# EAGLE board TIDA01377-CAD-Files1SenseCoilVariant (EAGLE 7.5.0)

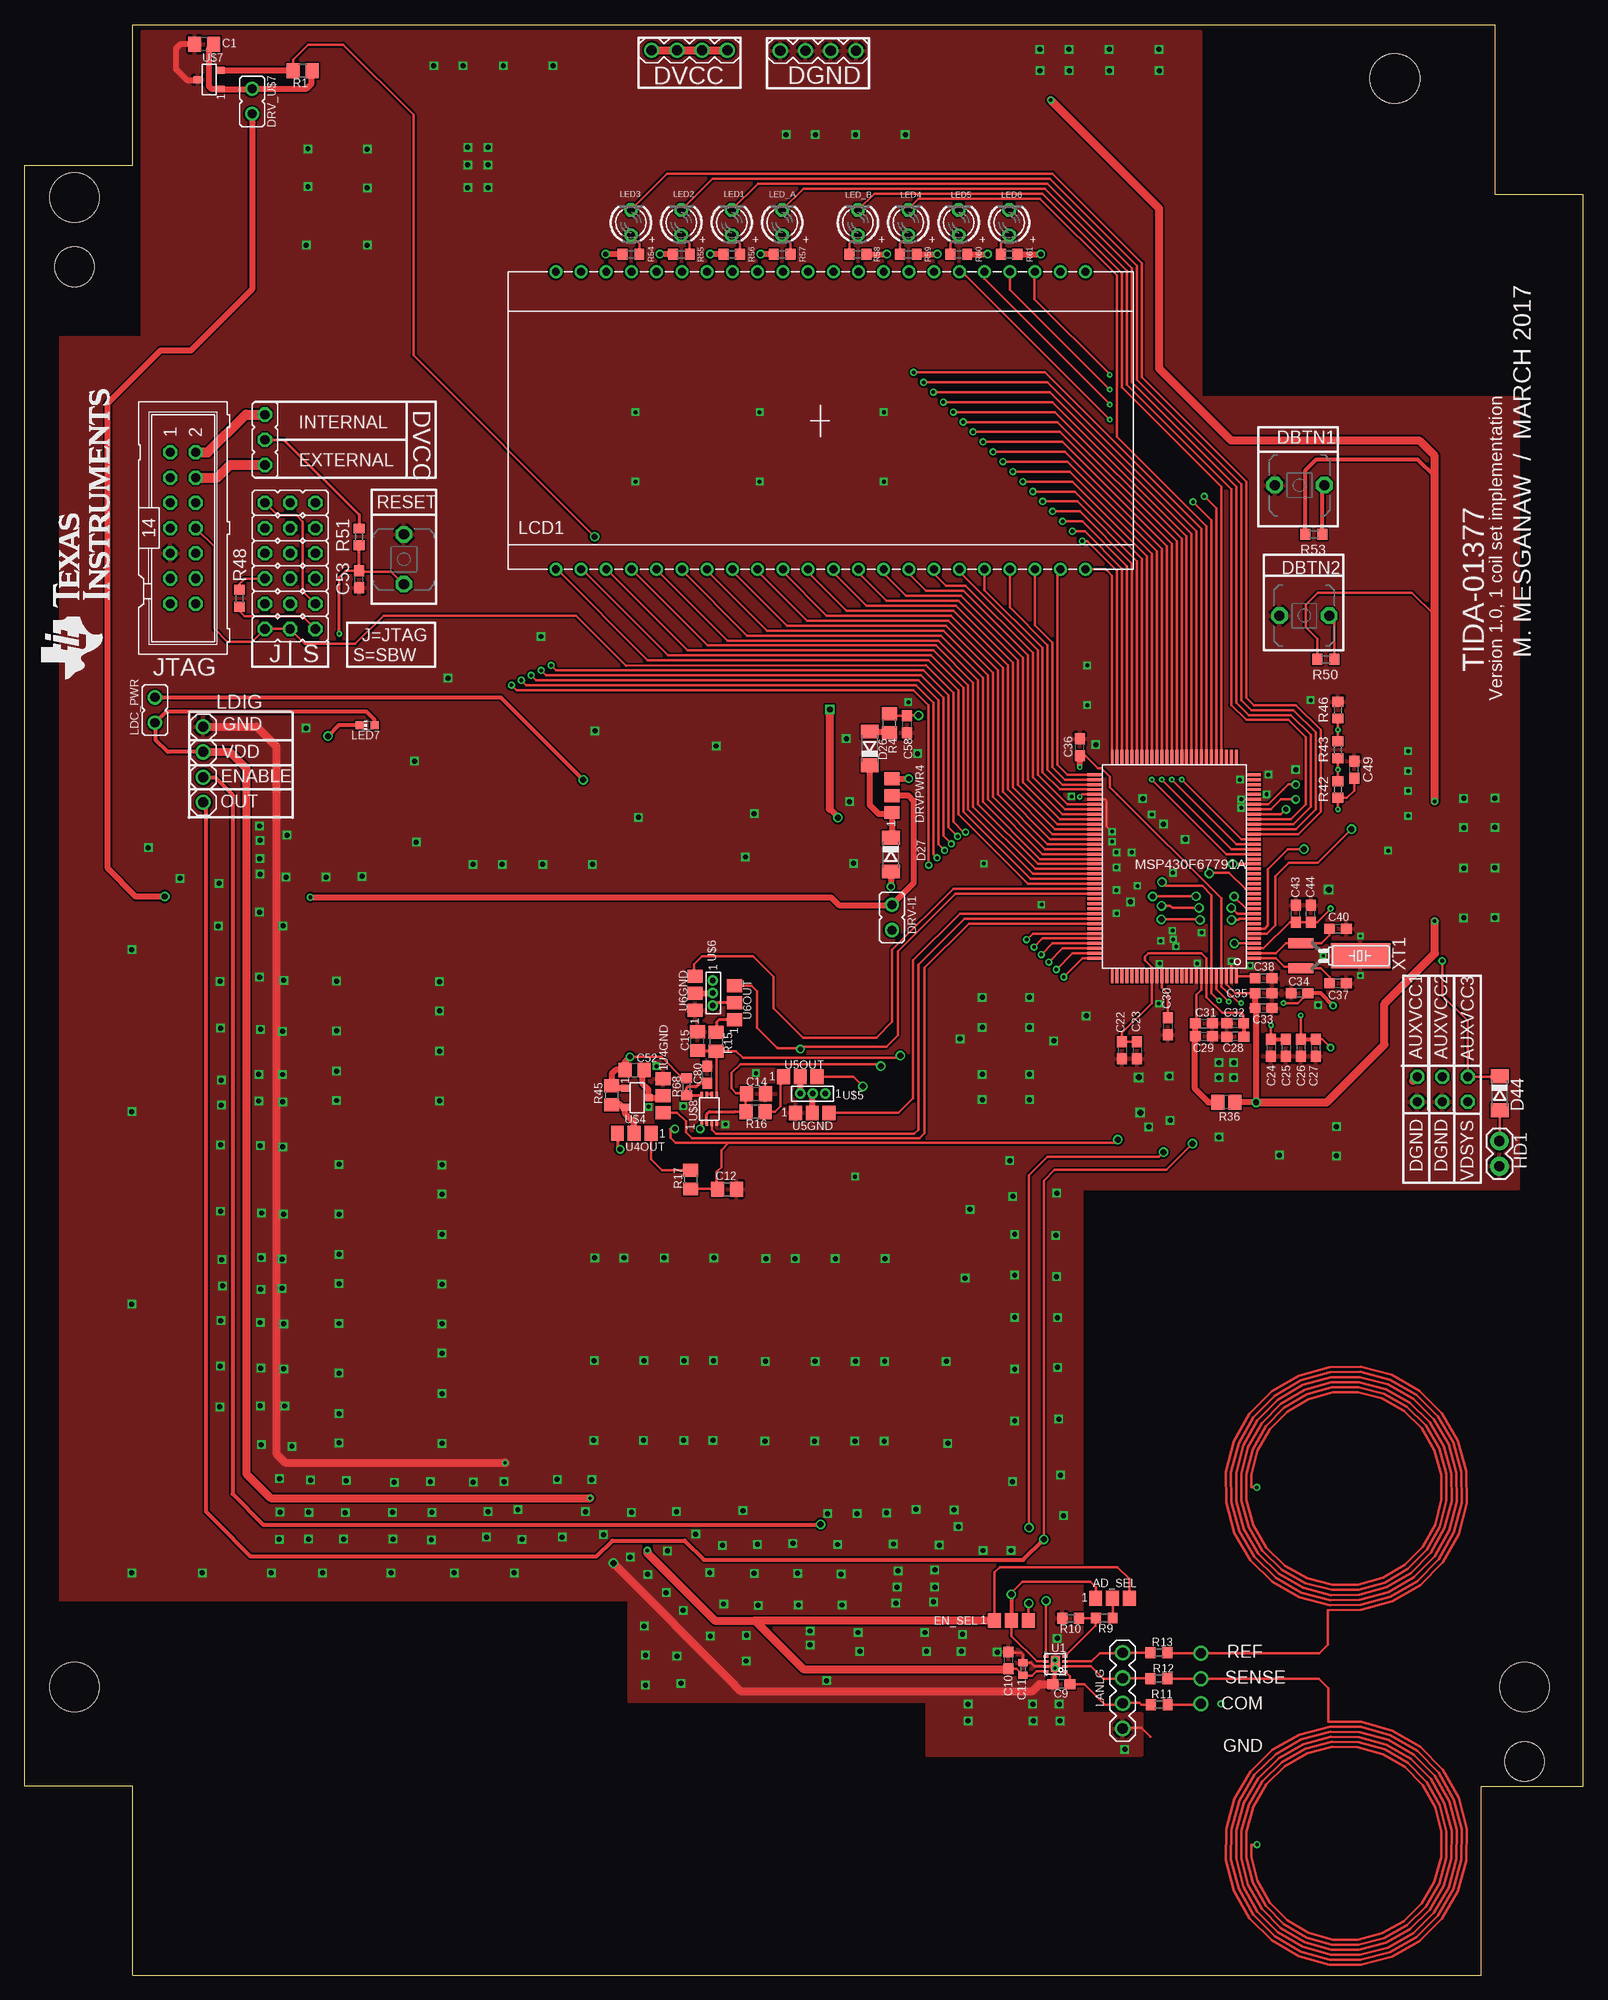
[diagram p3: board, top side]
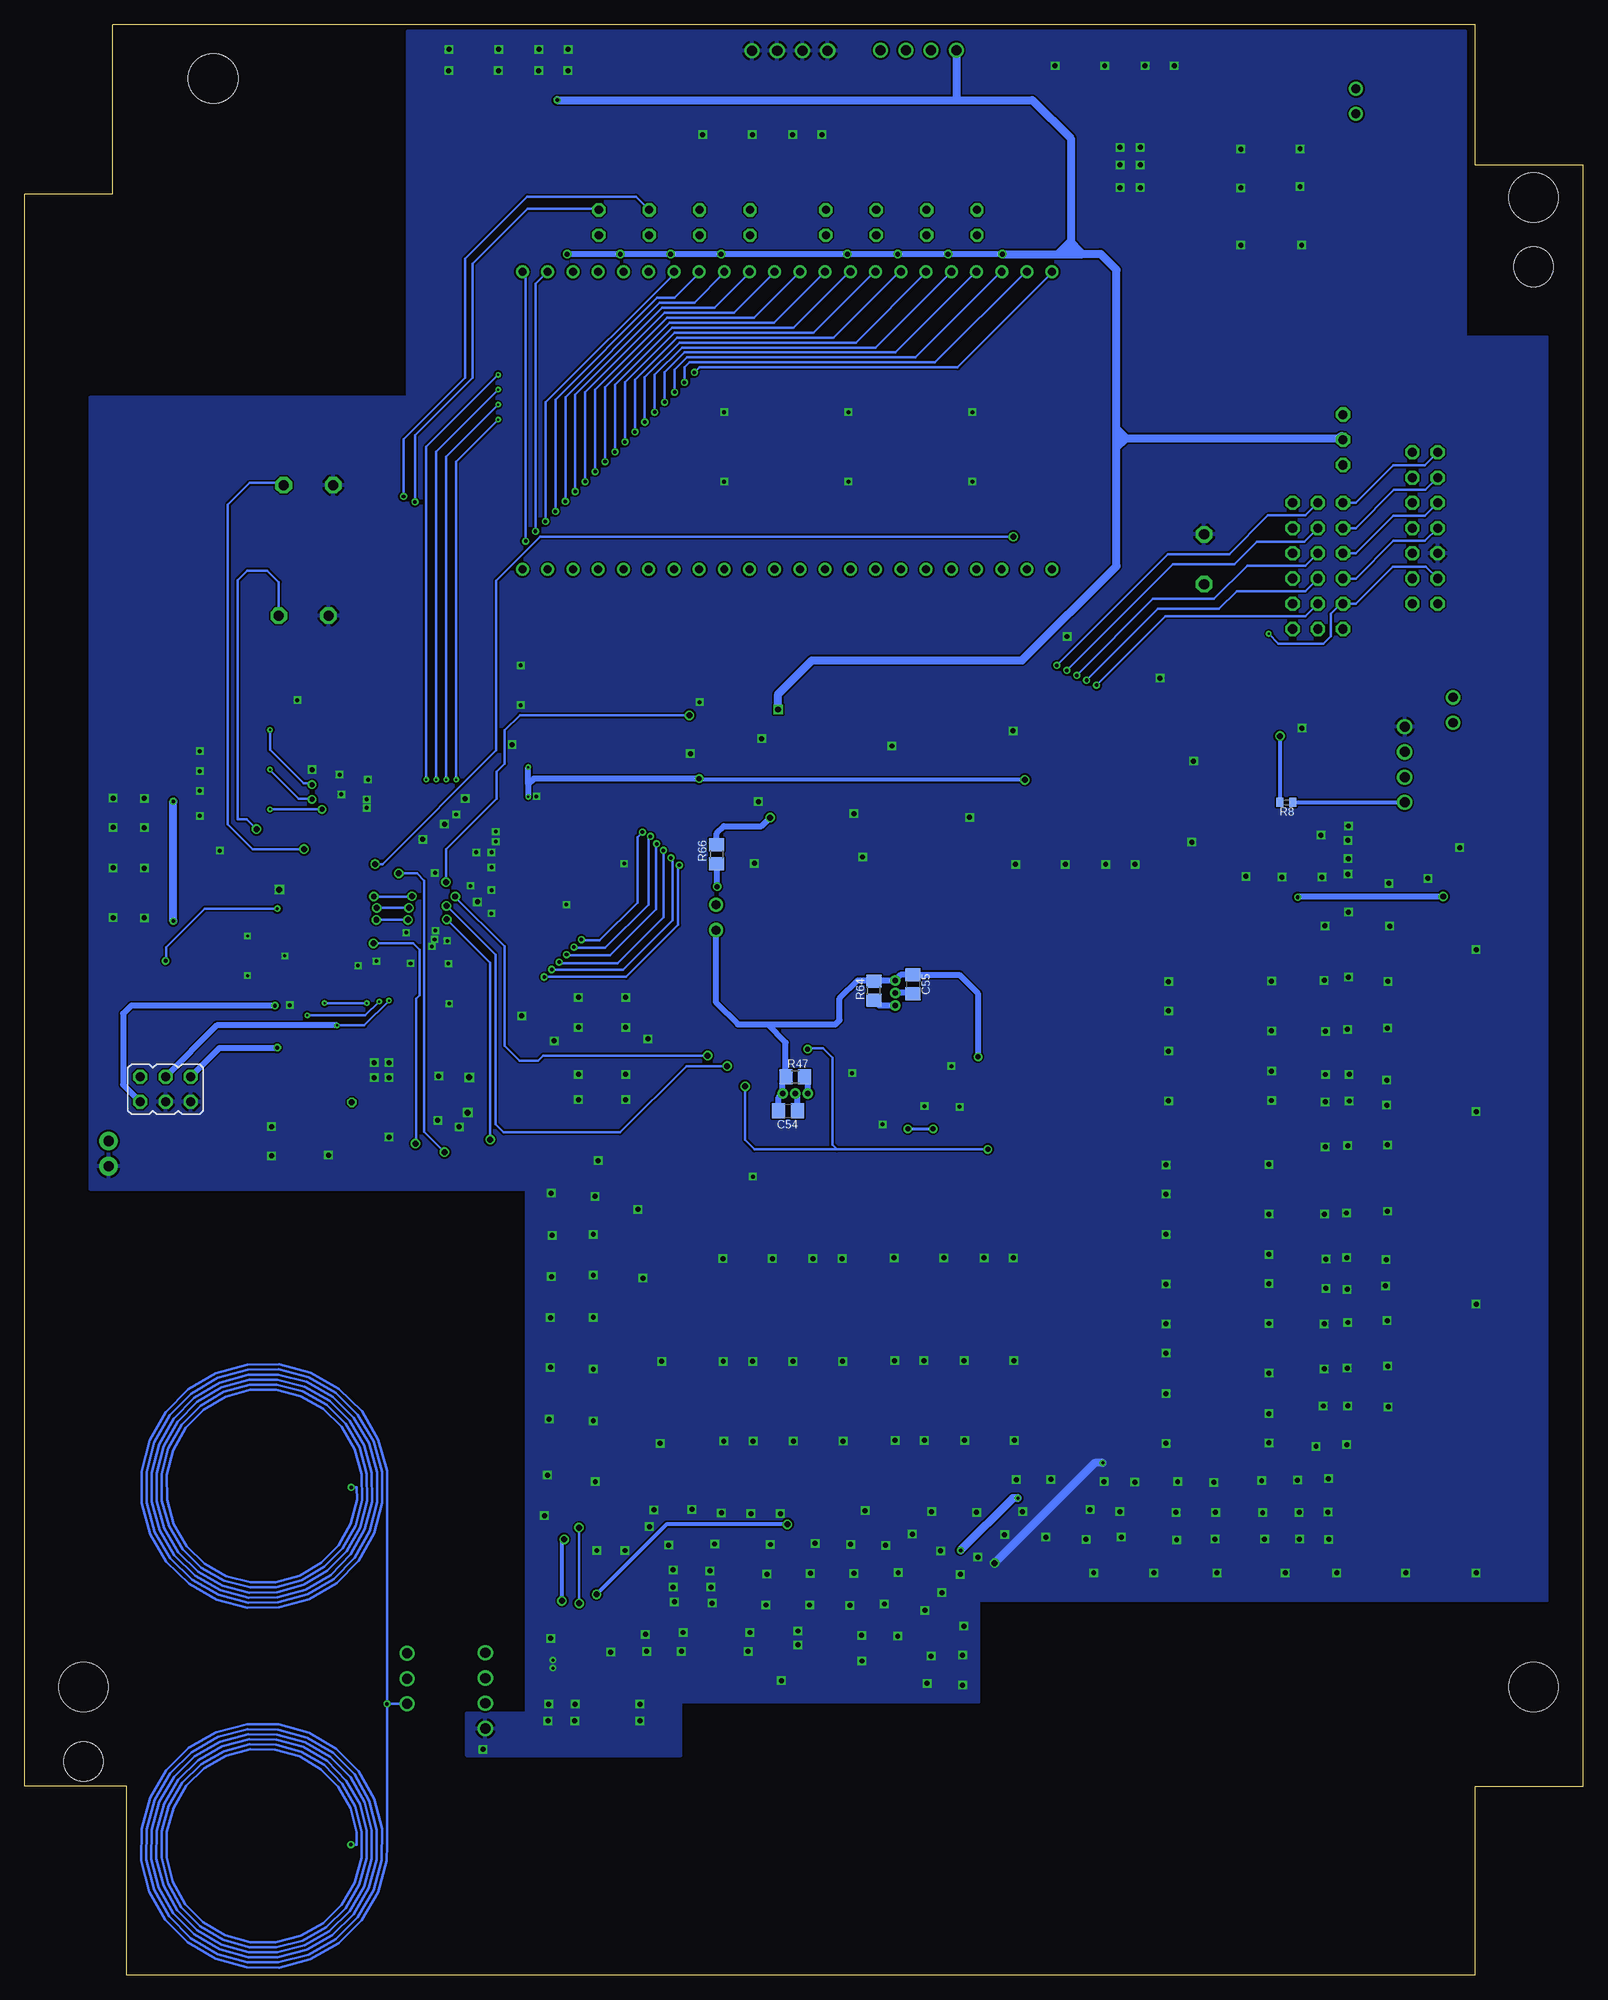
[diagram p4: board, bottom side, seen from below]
Size 156.94 x 196.36 mm. Coordinates in mm from the lower left corner, seen from the top.
Outline: 146.68,0 146.68,19 156.94,19 156.94,179.29 148.1,179.29 148.1,196.36 10.88,196.36 10.88,182.2 0,182.2 0,19 10.88,19 10.88,0 146.68,0
Copper layers (1*16): Top 0.0356mm / dielectric 1.5011mm / Bottom 0.0356mm
Design rules "SilverCircuits *": minimum track width 7mil, minimum drill 7.5mil, track to track 7mil, track to pad 7mil, pad to pad 7mil, via to via 7mil, smd to smd 0mil, copper to edge 20mil, drill to drill 8mil, minimum pad ring 10mil, minimum via ring 7mil, stop-mask expansion 4mil, vias tented up to drill 17mil, thermal gap 10mil
Holes 5 mm at 137.97,190.95 5,178.99 5,29 151.04,29
Holes 4 mm at 5,172 151.04,21.5

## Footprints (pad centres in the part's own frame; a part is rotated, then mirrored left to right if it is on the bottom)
A0R-JMP = smd 1.5 x 1.3: 1 0,1.7; 2 0,0; 3 0,-1.7
C0805 = smd 1.3 x 1.5: 1 -0.95,0; 2 0.95,0
C0603 = smd 1.1 x 1: 1 -0.85,0; 2 0.85,0
C0402 = smd 0.7 x 0.9: 1 -0.65,0; 2 0.65,0
SOD80C = smd 1.4 x 1.8: A 1.7,0; C -1.7,0
PBTH = drill 1.016 pad 1.676 octagon: 1 -0.001,0.001; 2 5.001,0.001
MA04-1 = drill 1.016: 1 -3.81,0; 2 -1.27,0; 3 1.27,0; 4 3.81,0
JP1 = drill 0.914: 1 0,-1.27; 2 0,1.27
1X02 = drill 1.016 pad 1.88: 1 0,0; 2 2.54,0
JP2 = drill 0.914 octagon: 1 -2.54,0; 2 0,0; 3 2.54,0
ML14 = drill 0.914 octagon: 1 -7.62,-1.27; 2 -7.62,1.27; 3 -5.08,-1.27; 4 -5.08,1.27; 5 -2.54,-1.27; 6 -2.54,1.27; 7 0,-1.27; 8 0,1.27; 9 2.54,-1.27; 10 2.54,1.27; 11 5.08,-1.27; 12 5.08,1.27; 13 7.62,-1.27; 14 7.62,1.27
TI_160SEG_LCD = drill 0.8: 1 4.826,0; 2 7.366,0; 3 9.906,0; 4 12.446,0; 5 14.986,0; 6 17.526,0; 7 20.066,0; 8 22.606,0; 9 25.146,0; 10 27.686,0; 11 30.226,0; 12 32.766,0; 13 35.306,0; 14 37.846,0; 15 40.386,0; 16 42.926,0; 17 45.466,0; 18 48.006,0; 19 50.546,0; 20 53.086,0; 21 55.626,0; 22 58.166,0; 23 58.166,29.972; 24 55.626,29.972; 29 42.926,29.972; 30 40.386,29.972; 31 37.846,29.972; 32 35.306,29.972; 33 32.766,29.972; 34 30.226,29.972; 35 27.686,29.972; 36 25.146,29.972; 37 22.606,29.972; 38 20.066,29.972; 39 17.526,29.972; 40 14.986,29.972; 41 12.446,29.972; 42 9.906,29.972; 43 7.366,29.972; 44 4.826,29.972; COM0 45.466,29.972; COM1 48.006,29.972; COM2 50.546,29.972; COM3 53.086,29.972
LED3MM = drill 0.813 octagon: A -1.27,0; K 1.27,0
CHIP-LED0603 = smd 0.8 x 0.8: A 0,-0.75; C 0,0.75
PEU128 = smd 0.3 x 1.4: 1 -9,-7.8; 2 -8.5,-7.8; 3 -8,-7.8; 4 -7.5,-7.8; 5 -7,-7.8; 6 -6.5,-7.8; 7 -6,-7.8; 8 -5.5,-7.8; 9 -5,-7.8; 10 -4.5,-7.8; 11 -4,-7.8; 12 -3.5,-7.8; 13 -3,-7.8; 14 -2.5,-7.8; 15 -2,-7.8; 16 -1.5,-7.8; 17 -1,-7.8; 18 -0.5,-7.8; 19 0,-7.8; 20 0.5,-7.8; 21 1,-7.8; 22 1.5,-7.8; 23 2,-7.8; 24 2.5,-7.8; 25 3,-7.8; 26 3.5,-7.8; 27 4,-7.8; 28 4.5,-7.8; 29 5,-7.8; 30 5.5,-7.8; 31 6,-7.8; 32 6.5,-7.8; 33 7,-7.8; 34 7.5,-7.8; 35 8,-7.8; 36 8.5,-7.8; 37 9,-7.8; 38 9.5,-7.8; 65 9.5,8.3; 66 9,8.3; 67 8.5,8.3; 68 8,8.3; 69 7.5,8.3; 70 7,8.3; 71 6.5,8.3; 72 6,8.3; 73 5.5,8.3; 74 5,8.3; 75 4.5,8.3; 76 4,8.3; 77 3.5,8.3; 78 3,8.3; 79 2.5,8.3; 80 2,8.3; 81 1.5,8.3; 82 1,8.3; 83 0.5,8.3; 84 0,8.3; 85 -0.5,8.3; 86 -1,8.3; 87 -1.5,8.3; 88 -2,8.3; 89 -2.5,8.3; 90 -3,8.3; 91 -3.5,8.3; 92 -4,8.3; 93 -4.5,8.3; 94 -5,8.3; 95 -5.5,8.3; 96 -6,8.3; 97 -6.5,8.3; 98 -7,8.3; 99 -7.5,8.3; 100 -8,8.3; 101 -8.5,8.3; 102 -9,8.3 | smd 1.4 x 0.3: 39 11.3,-6; 40 11.3,-5.5; 41 11.3,-5; 42 11.3,-4.5; 43 11.3,-4; 44 11.3,-3.5; 45 11.3,-3; 46 11.3,-2.5; 47 11.3,-2; 48 11.3,-1.5; 49 11.3,-1; 50 11.3,-0.5; 51 11.3,0; 52 11.3,0.5; 53 11.3,1; 54 11.3,1.5; 55 11.3,2; 56 11.3,2.5; 57 11.3,3; 58 11.3,3.5; 59 11.3,4; 60 11.3,4.5; 61 11.3,5; 62 11.3,5.5; 63 11.3,6; 64 11.3,6.5; 103 -10.8,6.5; 104 -10.8,6; 105 -10.8,5.5; 106 -10.8,5; 107 -10.8,4.5; 108 -10.8,4; 109 -10.8,3.5; 110 -10.8,3; 111 -10.8,2.5; 112 -10.8,2; 113 -10.8,1.5; 114 -10.8,1; 115 -10.8,0.5; 116 -10.8,0; 117 -10.8,-0.5; 118 -10.8,-1; 119 -10.8,-1.5; 120 -10.8,-2; 121 -10.8,-2.5; 122 -10.8,-3; 123 -10.8,-3.5; 124 -10.8,-4; 125 -10.8,-4.5; 126 -10.8,-5; 127 -10.8,-5.5; 128 -10.8,-6
R0805 = smd 1.3 x 1.5: 1 -0.95,0; 2 0.95,0
R0402 = smd 0.7 x 0.9: 1 -0.65,0; 2 0.65,0
R0603 = smd 1 x 1.1: 1 -0.85,0; 2 0.85,0
R0805' = smd 1.3 x 1.5: 1 -0.85,0; 2 0.85,0
JP3Q = drill 0.914 octagon: 1 -2.54,-1.27; 2 -2.54,1.27; 3 0,-1.27; 4 0,1.27; 5 2.54,-1.27; 6 2.54,1.27
DSG0008A = smd 0.508 x 0.254: 1 -0.95,0.75; 2 -0.95,0.25; 3 -0.95,-0.25; 4 -0.95,-0.75; 5 0.95,-0.75; 6 0.95,-0.25; 7 0.95,0.25; 8 0.95,0.75 | smd 0.889 x 1.6: 9 0,0
SOT23 = smd 0.7 x 0.8: 1 -0.92,-2.07; 2 0.98,-2.07; 3 0.03,0.275
SIP = drill 0.55: 1 0,0; 2 1.27,0; 3 2.54,0
DCU = smd 0.5 x 0.25: 1 1.39,-0.95; 2 1.39,-1.45; 3 1.39,-1.95; 4 1.39,-2.45; 5 4.29,-2.45; 6 4.29,-1.95; 7 4.29,-1.45; 8 4.29,-0.95
CM200T = smd 1 x 2.5: P1 -1.25,-5; P2 1.25,-5 | smd 2.5 x 6: P3 0,1

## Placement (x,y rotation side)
AD_SEL  0R-JUMPA  [A0R-JMP]  109.55,37.96 270 top
C1  DNP  [C0805]  18.06,194.4 180 top
C9  27pF  [C0603]  104.39,29.3 180 top
C10  1u  [C0603]  99.08,31.69 90 top
C11  0.1u  [C0402]  100.53,30.83 90 top
C12  DNP  [C0805]  70.71,79.14 0 top
C14  DNP  [C0805]  73.63,88.74 0 top
C15  DNP  [C0805]  67.74,94.05 90 top
C22  4.7uF  [C0603]  110.51,93.12 270 top
C23  100nF  [C0603]  112.01,93.12 270 top
C24  4.7uF  [C0603]  125.51,93.38 270 top
C25  100nF  [C0603]  127.01,93.38 270 top
C26  4.7uF  [C0603]  128.51,93.38 270 top
C27  100nF  [C0603]  130.01,93.38 270 top
C28  100nF  [C0603]  121.91,94.5 180 top
C29  4.7uF  [C0603]  118.76,94.53 0 top
C30  100nF  [C0603]  115.11,95.53 270 top
C31  100nF  [C0603]  118.76,95.83 0 top
C32  4.7uF  [C0603]  121.9,95.83 180 top
C33  100nF  [C0603]  124.76,97.38 0 top
C34  4.7uF  [C0603]  128.38,98.88 180 top
C35  4.7uF  [C0603]  124.76,98.88 0 top
C36  100nF  [C0603]  106.26,123.62 90 top
C37  12pF  [C0603]  132.26,99.88 0 top
C38  0.47uF  [C0603]  124.76,100.38 0 top
C40  12pF  [C0603]  132.26,105.38 0 top
C43  100nF  [C0603]  128.01,106.88 90 top
C44  0.47uF  [C0603]  129.51,106.88 90 top
C49  4.7uF  [C0603]  133.88,121.38 90 top
C52  DNP  [C0805]  61.4,91.14 0 top
C53  0.1uF  [C0603]  33.67,140.56 90 top
C54  DNP  [C0805]  80.08,87.02 0 bottom
C55  DNP  [C0805]  67.51,99.77 270 bottom
C58  DNP  [C0603]  88.82,125.95 270 top
C80  DNP  [C0603]  68.73,90.67 90 top
D26  PMLL4148  [SOD80C]  85.09,123.51 90 top
D27  PMLL4148  [SOD80C]  87.22,112.82 270 top
D44  [SOD80C]  148.54,88.79 270 top
DBTN1  [PBTH]  125.88,150.02 0 top
DBTN2  [PBTH]  126.36,136.88 0 top
DGND  [MA04-1]  79.9,193.75 0 top
DRV-I1  [JP1]  87.32,106.49 0 top
DRV_U$7  [JP1]  22.88,188.66 180 top
DRVPWR4  0R-JUMPA  [A0R-JMP]  87.32,118.76 0 top
DVCC  [MA04-1]  66.94,193.8 0 top
EN_SEL  0R-JUMPA  [A0R-JMP]  99.36,35.7 270 top
HD1  [1X02]  148.51,81.45 90 top
JP4  [JP2]  26.72,135.54 180 top
JP5  [JP2]  26.72,138.08 180 top
JP6  [JP2]  26.72,140.62 180 top
JP7  [JP2]  26.72,143.16 180 top
JP8  [JP2]  26.72,145.7 180 top
JP9  [JP2]  26.72,148.24 180 top
JP10  [JP2]  24.18,154.59 270 top
JTAG  [ML14]  15.93,145.7 270 top
LANLG  [MA04-1]  110.56,28.64 90 top
LCD1  TI_160SEG_LCD  [TI_160SEG_LCD]  48.65,141.53 0 top
LDC_PWR  [JP1]  13.1,127.37 0 top
LDIG  [MA04-1]  17.98,121.89 90 top
LED1  [LED3MM]  71.2,176.46 90 top
LED2  [LED3MM]  66.12,176.46 90 top
LED3  [LED3MM]  61.04,176.46 90 top
LED4  [LED3MM]  88.98,176.46 90 top
LED5  [LED3MM]  94.06,176.46 90 top
LED6  [LED3MM]  99.14,176.46 90 top
LED7  [CHIP-LED0603]  34.47,125.85 90 top
LED_A  [LED3MM]  76.28,176.46 90 top
LED_B  [LED3MM]  83.9,176.46 90 top
MSP430F67791A  MSP430F6779AIPEU  [PEU128]  116.01,111.38 90 top
R1  DNP  [R0805]  27.99,191.74 180 top
R4  DNP  [R0805]  87.07,126.05 90 top
R8  200  [R0402]  29.89,118.08 180 bottom
R9  49.9k  [R0603]  108.71,35.96 0 top
R10  9.31k(One Sense Coil); 44.2k(Two Sense Coil)  [R0603]  105.33,35.93 0 top
R11  0  [R0603]  114.25,27.25 0 top
R12  0  [R0603]  114.22,29.84 0 top
R13  0  [R0603]  114.22,32.48 0 top
R15  DNP  [R0805]  69.62,93.97 90 top
R16  DNP  [R0805]  73.58,86.94 0 top
R17  DNP  [R0805]  67.05,80.1 90 top
R36  10R  [R0805']  121.02,87.89 180 top
R42  560k  [R0603]  132.26,119.38 270 top
R43  560k  [R0603]  132.26,123.38 270 top
R45  DNP  [R0805]  59.11,88.58 270 top
R46  560k  [R0603]  132.26,127.38 270 top
R47  DNP  [R0805]  79.35,90.45 0 bottom
R48  330  [R0603]  21.62,138.62 270 top
R50  100K  [R0603]  131.04,132.48 0 top
R51  47K  [R0603]  33.67,144.81 270 top
R53  100K  [R0603]  129.82,145.06 0 top
R54  100  [R0603]  61.04,173.28 0 top
R55  100  [R0603]  66.12,173.28 0 top
R56  100  [R0603]  71.2,173.28 0 top
R57  100  [R0603]  76.28,173.28 0 top
R58  100  [R0603]  83.9,173.28 180 top
R59  100  [R0603]  88.98,173.28 180 top
R60  100  [R0603]  94.06,173.28 180 top
R61  100  [R0603]  99.14,173.28 180 top
R64  DNP  [R0805]  71.44,99.11 270 bottom
R66  DNP  [R0805]  87.27,112.87 90 bottom
R68  DNP  [R0603]  66.62,89.45 90 top
RESET  [PBTH]  38.17,140.06 90 top
SV1  [JP3Q]  142.77,89.2 0 bottom
U1  Value  [DSG0008A]  103.78,31.34 180 top
U4GND  0R-JUMPA  [A0R-JMP]  64.29,88.54 180 top
U4OUT  0R-JUMPA  [A0R-JMP]  61.37,84.78 90 top
U5GND  0R-JUMPA  [A0R-JMP]  79.31,86.81 270 top
U5OUT  0R-JUMPA  [A0R-JMP]  78.09,90.44 270 top
U6GND  0R-JUMPA  [A0R-JMP]  67.51,98.86 0 top
U6OUT  0R-JUMPA  [A0R-JMP]  71.48,97.9 0 top
U$4  DRV5033_SOT23  [SOT23]  62.53,88.38 270 top
U$5  DRV5033_SIP  [SIP]  80.62,88.78 180 top
U$6  DRV5033_SIP  [SIP]  69.29,100.16 270 top
U$7  DRV5033_SOT23  [SOT23]  17.68,190.82 90 top
U$8  SN74AUP2G32  [DCU]  67.23,84.38 90 top
XT1  [CM200T]  133.51,102.62 270 top

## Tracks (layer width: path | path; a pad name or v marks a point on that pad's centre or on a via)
ADJ
  Top 0.254: R10.2 107.83,35.93 R9.1 | 107.9,35.92 R9.1 | U1.4 107.82,35.17 107.82,35.92 R9.1
AUXVCC1  (via drill 0.2, 0.4)
  Top 0.254: MSP430F67791A.124 120.01,99.28 v121.26,98.03 | v128.51,96.62 C26.1 | C27.1 130.66,94.22 v131.51,93.38
  Top 0.406: C26.1 128.51,93.88 128.86,94.22 C27.1
  Top 0.813: 139.8,90.03 SV1.6
  Bottom 0.254: v128.51,96.62 122.66,96.62 v121.26,98.03
  Bottom 0.61: v131.51,93.38 131.47,93.34 137.36,93.34 SV1.6
AUXVCC2  (via drill 0.2, 0.6)
  Top 0.254: v120.26,98.12 119.51,98.88 MSP430F67791A.123 119.51,108.75 118.59,109.67 114.91,109.67 v114.53,110.05 | C24.1 v125.51,95.62 | v90.02,126.84 88.86,126.84 C58.1 87.27,126.8 R4.2
  Top 0.406: C24.1 125.51,94.38 125.66,94.22 C25.1
  Bottom 0.254: v125.51,95.62 122.76,95.62 v120.26,98.12 | v90.02,126.84 90.04,126.86 107.08,126.86 108.61,125.34 108.61,121.99 109.42,121.17 109.42,118.46 114.53,113.35 v114.53,110.05
  Bottom 0.61: v125.51,95.62 137.61,95.62 SV1.4
AUXVCC3  (via drill 0.3, 0.4)
  Top 0.254: C43.1 128.13,106 | MSP430F67791A.3 124.76,103.38 127.41,106.03 C43.1 | C43.1 128.01,105.88 128.16,106.03 C44.1 130.16,106.03 v131.51,107.38 | v142.76,102.12 142.76,98.62 145.31,96.07 SV1.2 148.51,90.47 D44.C
  Bottom 0.254: v131.51,107.38 138.81,107.38 142.71,103.47 142.71,102.17 v142.76,102.12 142.81,102.07
AVCC
  Top 0.254: 117.76,94.62 117.86,94.53 C29.1 | 118.01,95.88 117.96,95.83 C31.1 | MSP430F67791A.121 118.51,99.2 118.01,98.7 118.01,95.83 C31.1 | C31.1 117.81,95.83 117.76,95.88 117.91,96.03
  Top 0.406: C29.1 118.01,94.62 117.91,94.72
  Top 0.61: 117.91,94.72 C31.1 | 117.86,94.53 117.86,89.22 119.2,87.89 R36.2
BTN1  (via drill 0.6)
  Top 0.254: MSP430F67791A.7 124.86,105.38 125.19,105.71 125.19,111.34 127.23,113.38 v128.83,113.38
  Top 0.406: R53.2 130.67,149.81 DBTN1.2
  Bottom 0.254: v128.83,113.38 134.01,113.38 136.51,115.88 136.51,148.04 134.29,150.26 131.12,150.26 DBTN1.2
BTN2  (via drill 0.6)
  Top 0.254: MSP430F67791A.6 125.1,104.88 125.96,105.73 125.96,110.63 127.33,112 130.22,112 v133.6,115.38 | R50.2 131.89,136.36 DBTN2.2
  Bottom 0.254: v133.6,115.38 134.59,116.38 135.51,116.38 135.51,140.45 134.54,141.42 132.54,141.42 131.36,140.25 DBTN2.2
COILS  (via drill 0.36 pad 0.58, 1.02 pad 1.52)
  Top 0.254: R12.2 v118.44,29.86 130.3,29.86 131.27,28.9 131.27,25.52 131.34,25.52 134.6,25.5 137.73,24.63 140.53,22.99 142.8,20.69 144.4,17.88 145.22,14.76 145.19,11.54 144.34,8.43 142.72,5.66 140.44,3.41 137.66,1.83 134.57,1.03 131.38,1.05 128.31,1.89 125.57,3.5 123.34,5.76 121.78,8.51 120.98,11.57 121,14.72 121.84,17.76 123.43,20.47 125.66,22.67 128.38,24.22 131.41,25.01 134.53,24.99 137.53,24.16 140.22,22.59 142.4,20.38 143.93,17.68 144.71,14.69 144.69,11.6 143.87,8.63 142.31,5.98 140.13,3.82 137.46,2.3 134.5,1.53 131.44,1.55 128.51,2.36 125.88,3.9 123.75,6.07 122.25,8.7 121.49,11.63 121.51,14.65 122.31,17.56 123.83,20.16 125.97,22.27 128.58,23.75 131.48,24.5 134.46,24.48 137.34,23.69 139.9,22.18 141.99,20.06 143.45,17.49 144.2,14.62 144.18,11.67 143.39,8.83 141.91,6.29 139.81,4.23 137.26,2.78 134.43,2.04 131.51,2.06 128.7,2.84 126.19,4.31 124.15,6.38 122.72,8.9 122,11.7 122.02,14.59 122.78,17.36 124.24,19.84 126.28,21.86 128.78,23.27 131.54,23.99 134.4,23.97 137.14,23.21 139.59,21.77 141.58,19.75 142.98,17.29 143.69,14.55 143.67,11.73 142.92,9.02 141.5,6.6 139.5,4.63 137.07,3.25 134.37,2.55 131.58,2.57 128.9,3.31 126.5,4.72 124.56,6.69 123.2,9.1 122.5,11.77 122.52,14.52 123.26,17.17 124.65,19.53 126.6,21.45 128.97,22.8 131.61,23.48 134.33,23.46 136.95,22.74 139.28,21.37 141.18,19.44 142.51,17.09 143.18,14.49 143.16,11.8 142.45,9.22 141.09,6.91 139.19,5.04 136.87,3.73 134.3,3.06 131.65,3.08 129.09,3.79 126.82,5.12 124.97,7 123.67,9.29 123.01,11.83 123.03,14.45 123.73,16.97 125.05,19.22 126.91,21.05 129.17,22.32 131.68,22.98 134.26,22.95 136.75,22.27 138.97,20.96 140.77,19.13 142.03,16.9 142.68,14.42 142.65,11.87 141.97,9.41 140.69,7.22 138.88,5.45 136.68,4.2 134.23,3.57 131.71,3.59 129.29,4.26 127.13,5.53 125.37,7.31 124.14,9.49 123.52,11.9 123.54,13.14 v124.1,13.14 v124.1,13.15
  Top 0.254: 115.17,32.38 R13.2 115.15,32.4 v118.44,32.4 130.38,32.4 131.24,33.27 131.24,36.75 131.34,36.75 134.6,36.77 137.73,37.63 140.53,39.27 142.8,41.58 144.4,44.39 145.22,47.51 145.19,50.73 144.34,53.83 142.72,56.6 140.44,58.85 137.66,60.43 134.57,61.24 131.38,61.22 128.31,60.37 125.57,58.77 123.34,56.51 121.78,53.76 120.98,50.7 121,47.54 121.84,44.51 123.43,41.8 125.66,39.59 128.38,38.05 131.41,37.26 134.53,37.28 137.53,38.1 140.22,39.68 142.4,41.89 143.93,44.58 144.71,47.58 144.69,50.66 143.87,53.63 142.31,56.29 140.13,58.44 137.46,59.96 134.5,60.73 131.44,60.71 128.51,59.9 125.88,58.36 123.75,56.2 122.25,53.56 121.49,50.63 121.51,47.61 122.31,44.7 123.83,42.11 125.97,40 128.58,38.52 131.48,37.76 134.46,37.78 137.34,38.58 139.9,40.08 141.99,42.2 143.45,44.78 144.2,47.64 144.18,50.59 143.39,53.44 141.91,55.98 139.81,58.04 137.26,59.48 134.43,60.22 131.51,60.2 128.7,59.43 126.19,57.95 124.15,55.88 122.72,53.36 122,50.56 122.02,47.68 122.78,44.9 124.24,42.42 126.28,40.41 128.78,38.99 131.54,38.27 134.4,38.29 137.14,39.05 139.59,40.49 141.58,42.51 142.98,44.97 143.69,47.71 143.67,50.53 142.92,53.24 141.5,55.66 139.5,57.63 137.07,59.01 134.37,59.71 131.58,59.69 128.9,58.95 126.5,57.55 124.56,55.57 123.2,53.17 122.5,50.5 122.52,47.75 123.26,45.1 124.65,42.73 126.6,40.81 128.97,39.47 131.61,38.78 134.33,38.8 136.95,39.52 139.28,40.9 141.18,42.82 142.51,45.17 143.18,47.77 143.16,50.46 142.45,53.05 141.09,55.35 139.19,57.22 136.87,58.54 134.3,59.21 131.65,59.18 129.09,58.48 126.82,57.14 124.97,55.26 123.67,52.97 123.01,50.43 123.03,47.81 123.73,45.29 125.05,43.04 126.91,41.22 129.17,39.94 131.68,39.29 134.26,39.31 136.75,40 138.97,41.3 140.77,43.14 142.03,45.37 142.68,47.84 142.65,50.4 141.97,52.85 140.69,55.04 138.88,56.82 136.68,58.06 134.23,58.7 131.71,58.68 129.29,58.01 127.13,56.73 125.37,54.95 124.14,52.78 123.52,50.36 123.54,49.12 124.1,49.12 v124.08,49.11
  Top 0.254: R11.2 118.36,27.25 v118.44,27.32
  Bottom 0.254: v120.47,27.32 120.47,13.14 120.49,11.5 121.36,8.34 123.02,5.51 125.35,3.21 128.19,1.59 131.34,0.77 134.6,0.79 137.73,1.65 140.53,3.29 142.8,5.6 144.4,8.41 145.22,11.53 145.19,14.75 144.34,17.85 142.72,20.62 140.44,22.87 137.66,24.46 134.57,25.26 131.38,25.24 128.31,24.4 125.57,22.79 123.34,20.53 121.78,17.78 120.98,14.72 121,11.57 121.84,8.53 123.43,5.82 125.66,3.62 128.38,2.07 131.41,1.28 134.53,1.3 137.53,2.13 140.22,3.7 142.4,5.91 143.93,8.61 144.71,11.6 144.69,14.69 143.87,17.66 142.31,20.31 140.13,22.47 137.46,23.98 134.5,24.75 131.44,24.73 128.51,23.92 125.88,22.38 123.75,20.22 122.25,17.58 121.49,14.66 121.51,11.63 122.31,8.73 123.83,6.13 125.97,4.02 128.58,2.54 131.48,1.79 134.46,1.81 137.34,2.6 139.9,4.11 141.99,6.22 143.45,8.8 144.2,11.66 144.18,14.62 143.39,17.46 141.91,20 139.81,22.06 137.26,23.51 134.43,24.25 131.51,24.22 128.7,23.45 126.19,21.98 124.15,19.91 122.72,17.39 122,14.59 122.02,11.7 122.78,8.92 124.24,6.44 126.28,4.43 128.78,3.02 131.54,2.3 134.4,2.32 137.14,3.07 139.59,4.51 141.58,6.54 142.98,9 143.69,11.73 143.67,14.55 142.92,17.27 141.5,19.69 139.5,21.66 137.07,23.04 134.37,23.74 131.58,23.72 128.9,22.98 126.5,21.57 124.56,19.6 123.2,17.19 122.5,14.52 122.52,11.77 123.26,9.12 124.65,6.76 126.6,4.84 128.97,3.49 131.61,2.8 134.33,2.82 136.95,3.55 139.28,4.92 141.18,6.85 142.51,9.19 143.18,11.8 143.16,14.49 142.45,17.07 141.09,19.38 139.19,21.25 136.87,22.56 134.3,23.23 131.65,23.21 129.09,22.5 126.82,21.16 124.97,19.29 123.67,17 123.01,14.46 123.03,11.84 123.73,9.32 125.05,7.07 126.91,5.24 129.17,3.96 131.68,3.31 134.26,3.33 136.75,4.02 138.97,5.33 140.77,7.16 142.03,9.39 142.68,11.87 142.65,14.42 141.97,16.87 140.69,19.06 138.88,20.84 136.68,22.09 134.23,22.72 131.71,22.7 129.29,22.03 127.13,20.76 125.37,18.97 124.14,16.8 123.52,14.39 123.54,13.14 v124.1,13.14 v124.1,13.15
  Bottom 0.254: v120.47,27.32 v118.44,27.32 | v120.47,27.32 120.45,49.12 120.47,50.76 121.34,53.93 122.99,56.76 125.32,59.05 128.16,60.67 131.32,61.49 134.57,61.47 137.7,60.61 140.5,58.97 142.78,56.66 144.38,53.85 145.19,50.73 145.17,47.51 144.32,44.41 142.69,41.64 140.41,39.39 137.63,37.81 134.54,37 131.35,37.02 128.28,37.87 125.54,39.47 123.32,41.73 121.75,44.48 120.95,47.54 120.98,50.7 121.81,53.73 123.4,56.44 125.63,58.65 128.36,60.2 131.38,60.98 134.5,60.96 137.51,60.14 140.19,58.56 142.37,56.35 143.9,53.66 144.68,50.66 144.66,47.58 143.84,44.61 142.29,41.95 140.1,39.8 137.43,38.28 134.47,37.51 131.42,37.53 128.48,38.34 125.86,39.88 123.72,42.04 122.23,44.68 121.46,47.61 121.48,50.63 122.28,53.54 123.81,56.13 125.95,58.24 128.55,59.72 131.45,60.48 134.44,60.45 137.31,59.66 139.88,58.16 141.96,56.04 143.43,53.46 144.17,50.6 144.15,47.64 143.37,44.8 141.88,42.26 139.79,40.2 137.24,38.75 134.41,38.02 131.49,38.04 128.68,38.81 126.17,40.29 124.13,42.36 122.7,44.88 121.97,47.67 121.99,50.56 122.76,53.34 124.21,55.82 126.26,57.83 128.75,59.25 131.52,59.97 134.37,59.95 137.12,59.19 139.57,57.75 141.56,55.73 142.96,53.27 143.67,50.53 143.64,47.71 142.9,45 141.47,42.58 139.48,40.61 137.04,39.23 134.34,38.53 131.55,38.55 128.87,39.29 126.48,40.69 124.54,42.67 123.17,45.07 122.48,47.74 122.5,50.49 123.23,53.14 124.62,55.51 126.57,57.43 128.95,58.77 131.58,59.46 134.3,59.44 136.92,58.72 139.26,57.34 141.15,55.42 142.48,53.07 143.16,50.46 143.14,47.78 142.42,45.19 141.07,42.89 139.16,41.02 136.85,39.7 134.27,39.03 131.62,39.05 129.07,39.76 126.79,41.1 124.94,42.98 123.65,45.27 122.99,47.81 123.01,50.43 123.7,52.95 125.03,55.2 126.88,57.02 129.14,58.3 131.65,58.95 134.24,58.93 136.72,58.24 138.94,56.94 140.75,55.1 142.01,52.87 142.65,50.4 142.63,47.84 141.95,45.39 140.66,43.2 138.85,41.42 136.65,40.17 134.21,39.54 131.69,39.56 129.26,40.23 127.1,41.51 125.35,43.29 124.12,45.46 123.49,47.88 123.52,49.12 v124.07,49.12 v124.08,49.11
COM0  (via drill 0.2)
  Top 0.254: MSP430F67791A.22 121.01,112.88 v113.51,120.38 | LCD1.COM0 94.38,171.5 v109.26,156.62
  Bottom 0.254: v113.51,120.38 113.51,152.38 v109.26,156.62
COM1  (via drill 0.2)
  Top 0.254: MSP430F67791A.23 121.51,113.38 v114.51,120.38 | v109.26,158.12 109.26,158.15 96.62,170.78 96.62,171.46 LCD1.COM1
  Bottom 0.254: v114.51,120.38 114.51,152.88 v109.26,158.12
COM2  (via drill 0.2)
  Top 0.254: MSP430F67791A.24 122.01,113.88 v115.51,120.38 | LCD1.COM2 99.2,169.68 v109.26,159.62
  Bottom 0.254: v115.51,120.38 115.51,153.38 v109.26,159.62
COM3  (via drill 0.2)
  Top 0.254: MSP430F67791A.25 122.51,114.38 v116.51,120.38 | v109.26,161.12 109.26,161.19 101.7,168.75 101.7,171.46 LCD1.COM3
  Bottom 0.254: v116.51,120.38 116.51,153.88 v109.26,161.12
DRESET  (via drill 0.36)
  Top 0.254: v49.01,129.88 49.51,129.38 89.51,129.38 91.01,127.88 91.01,111.77 v91.03,111.75 | MSP430F67791A.102 106.51,102.38 v104.63,100.5
  Bottom 0.254: JP5.2 27.99,136.81 42.08,136.81 v49.01,129.88 | v104.63,100.5 96.38,100.5 91.13,105.75 91.13,111.65 v91.03,111.75
DRV4GND
  Top 0.254: MSP430F67791A.95 95.09,105.88 90.63,101.41 90.63,84.78 90.09,84.24 67.21,84.24 66.57,84.88 66.57,85.97 65.7,86.84 U4GND.1
DRV5GND
  Top 0.254: MSP430F67791A.93 94.16,106.88 89.46,102.18 89.46,88.28 87.98,86.81 U5GND.1
DRV6GND
  Top 0.254: MSP430F67791A.88 93.51,109.38 87.35,103.22 87.35,95.98 85.77,94.4 78.36,94.4 75.39,97.38 75.39,100.53 73.33,102.58 68.2,102.58 67.41,101.8 67.41,100.67 U6GND.1
DRV456OUTA  (via drill 0.5, 0.6)
  Top 0.254: MSP430F67791A.89 93.74,108.88 87.93,103.06 87.93,94.66 86.76,93.49 78.36,93.49 v78.1,93.23 78.03,93.31 75.84,93.31 75.79,93.36 75.77,93.36 73.73,95.39 73.73,99.05 73.19,99.6 U6OUT.1 | U5OUT.1 83.44,90.44 v84.4,89.48
  Top 0.305: U4OUT.1 59.67,83.44 v59.97,83.15 | 79.82,90.42 U5OUT.1
  Bottom 0.254: v59.97,83.15 75.16,83.15 | v84.4,89.48 84.4,84.09 83.46,83.15 75.16,83.15 | 75.16,83.15 75.61,83.61 75.61,92.35 76.58,93.31 78.03,93.31 v78.1,93.23
DRV456OUTB
  Top 0.254: MSP430F67791A.94 94.62,106.38 89.99,101.74 89.99,85.13 89.56,84.7 69.59,84.7 69.19,85.11 U$8.3
DRVOUT4  (via drill 0.5, 0.6)
  Top 0.254: U$8.1 | 70.86,83.79 65.56,83.79 65.02,84.32 65.02,85.21 | 70.86,83.79 109.75,83.79 v110.08,84.12 | v114.45,106.29 118.31,106.29 v118.36,106.24 | v121.54,106.24 122.2,106.24 122.33,106.38 MSP430F67791A.9 | 68.03,79.15 R17.1 69.75,79.15 C12.1 69.67,79.23 69.67,80.87 70.15,81.35 70.15,83.08 70.86,83.79
  Top 0.305: U$8.1 68.17,85.36 v68.02,85.21 | v65.48,85.21 65.02,85.21
  Bottom 0.254: v110.08,84.12 110.08,101.92 v114.45,106.29 | v118.36,106.24 v121.54,106.24
  Bottom 0.305: v68.02,85.21 v65.48,85.21
DRVOUT5  (via drill 0.6)
  Top 0.254: 86.15,91.58 v86.21,91.53 86,91.74 72.06,91.74 71.17,90.85 71.17,89.3 71.65,88.81 72.61,88.81 C14.1 72.58,88.64 72.58,86.99 R16.1 71.55,86.94 | MSP430F67791A.10 123.78,106.85 122.12,106.85 v121.51,107.46 | v118.26,107.46 115.57,107.46 115.34,107.69 114.5,107.69 v114.48,107.66
  Top 0.305: U$8.2 68.68,86.66 68.96,86.94 71.55,86.94
  Bottom 0.254: v86.21,91.53 90.32,91.53 97,84.85 108.71,84.85 109.55,85.69 109.55,102.73 v114.48,107.66 | v121.51,107.46 v118.26,107.46
DRVOUT6  (via drill 0.6)
  Top 0.254: v117.96,108.63 113.61,108.63 v113.59,108.6 | U$8.5 69.68,92.96 R15.1 69.63,93.03 71.63,93.03 72.31,92.35 87.96,92.35 v88.19,92.57 | MSP430F67791A.11 123.02,107.38 v121.79,108.6
  Top 0.305: R15.1 67.82,93.02 C15.1
  Bottom 0.254: v117.96,108.63 117.98,108.6 v121.79,108.6 | v113.59,108.6 113.59,108.55 108.61,103.57 108.61,93.56 107.11,92.07 105.26,92.07 104.75,92.57 v88.19,92.57
DRVPOWER1
  Top 0.61: R1.1 28.88,191.68 28.88,190.44 28.37,189.93 DRV_U$7.1 22.85,189.9 U$7.1 18.82,189.9 18.57,190.16 18.57,193.96 C1.1
DRVPOWER4  (via drill 0.5)
  Top 0.254: v60.93,92.45 64.11,92.45 66.25,90.3 R68.2
  Top 0.61: 59.25,89.58 R45.1 | R45.1 59.11,89.8 | v60.93,92.45 60.45,91.96 C52.1 59.5,91.14 59.1,90.75 59.1,89.44 R45.1 | U$4.1 59.24,89.3 R45.1
  Bottom 0.305: 71.34,100.16 R64.1
  Bottom 0.61: 82.14,95.72 85.14,95.72 87.32,97.91 DRV-I1.1 | C54.1 81.03,88.37 U$5.1 80.62,89.94 80.67,89.98 R47.1 80.31,90.56 80.31,93.89 82.14,95.72 | 71.34,100.16 U$6.1 68.74,100.72 C55.1 62.83,100.72 60.96,98.85 60.96,92.47 v60.93,92.45 | R64.1 71.55,100.17 73.05,100.17 74.88,98.33 74.88,96.16 75.32,95.72 82.14,95.72
DRVU7  (via drill 0.6)
  Top 0.254: R1.2 27.04,192.87 28.55,194.38 32.05,194.38 39.14,187.29 39.14,163.09 v57.4,144.82 | MSP430F67791A.20 121.69,111.88 v121.66,111.85
  Top 0.61: U$7.2 26.97,191.8 R1.2
  Bottom 0.254: v57.4,144.82 105.05,144.82 109.47,140.4 109.47,123.31 120.93,111.85 v121.66,111.85
DTCK  (via drill 0.36)
  Top 0.254: v50.01,130.38 50.51,129.88 89.76,129.88 91.51,128.12 91.51,112.88 v91.88,112.5 | MSP430F67791A.101 105.51,102.88 v103.88,101.25
  Bottom 0.254: JP6.2 27.99,139.35 34.88,139.35 36.67,137.56 42.83,137.56 v50.01,130.38 | v103.88,101.25 96.68,101.25 91.72,106.21 91.72,112.33 v91.88,112.5
DTDI  (via drill 0.36)
  Top 0.254: v52.01,131.38 52.51,130.88 90.26,130.88 92.51,128.62 92.51,114.7 v93.31,113.9 | MSP430F67791A.99 103.51,103.88 v102.38,102.75
  Bottom 0.254: JP8.2 28.08,144.34 32.84,144.34 35.13,142.05 41.33,142.05 v52.01,131.38 | v102.38,102.75 102.34,102.71 98.02,102.71 93.38,107.34 93.38,113.82 v93.31,113.9
DTDO  (via drill 0.36)
  Top 0.254: v53.01,131.88 53.51,131.38 90.51,131.38 93.01,128.88 93.01,115.57 v93.93,114.65 | MSP430F67791A.98 102.51,104.38 v101.63,103.5
  Bottom 0.254: JP9.2 27.99,146.97 31.74,146.97 35.64,143.07 39.67,143.07 | 39.67,143.07 39.7,143.07 | 39.67,143.07 39.69,143.06 41.83,143.06 v53.01,131.88 | v101.63,103.5 101.55,103.42 98.5,103.42 94.13,107.79 94.13,114.44 v93.93,114.65
DTMS  (via drill 0.36)
  Top 0.254: v51.01,130.88 51.51,130.38 90.01,130.38 92.01,128.38 92.01,113.88 v92.63,113.25 | MSP430F67791A.100 104.51,103.38 v103.13,102
  Bottom 0.254: JP7.2 27.99,141.89 33.84,141.89 37.17,138.56 43.33,138.56 v51.01,130.88 | v92.63,113.25 92.63,106.49 97.23,101.9 103.03,101.9 v103.13,102
DVCC  (via drill 0.36, 0.36 pad 0.58, 0.5, 0.6)
  Top 0.254: MSP430F67791A.126 121.01,99.78 121.91,98.88 C35.1 | R50.1 130.19,134.54 129.03,135.7 129.03,137.99 130.22,139.18 139.7,139.18 141.98,136.9
  Top 0.305: R51.1 33.67,147.06 26.09,154.59 JP10.2
  Top 0.406: 123.51,97.38 C33.1 124.01,97.28 | R53.1 128.97,151.49 130.1,152.62 140.26,152.62 141.98,150.89
  Top 0.61: 124.01,97.28 v124.01,87.88 121.88,87.88 | C33.1 C35.1 | 58.4,173.38 v58.5,173.28 R54.1 | R55.1 v63.95,173.28 | R56.1 v69.03,173.28 | R57.1 v74.11,173.28 | R58.1 v86.81,173.28 | R59.1 v91.89,173.28 | R60.1 v96.97,173.28 | R61.1 v102.31,173.28 | v81.89,116.55 81.89,116.62 81.09,117.42
  Top 0.813: DVCC.1 DVCC.2 DVCC.3 DVCC.4 | 121.88,87.88 R36.1 | 124.05,87.92 v124.01,87.88 131.11,87.88 136.93,93.69 136.93,97.8 142.01,102.88 142.01,106.09 v141.98,106.11 | 81.09,117.42 v81.09,127.43 | v81.09,127.43 | v103.33,188.79 114.24,177.88 114.24,161.77 121.49,154.53 140.43,154.53 141.98,152.98 141.98,150.89 141.98,136.9 v141.98,118.18
  Bottom 0.61: v102.31,173.28 v96.97,173.28 v91.89,173.28 v86.81,173.28 v74.11,173.28 v69.03,173.28 v63.95,173.28 v58.5,173.28 | R66.2 87.27,114.95 86.54,115.69 82.75,115.69 v81.89,116.55
  Bottom 0.813: 47.01,154.05 47.01,171.69 48.61,173.3 48.63,173.28 50.43,173.28 | v81.09,127.43 81.09,128.97 77.69,132.38 56.51,132.38 47.01,141.88 47.01,154.05 | JP10.2 24.18,154.57 24.17,154.56 | v141.98,106.11 v141.98,118.18 | 24.33,154.73 46.05,154.73 46.19,154.87 | v103.33,188.79 62.94,188.79 | 62.94,188.79 55.47,188.79 51.61,184.93 51.61,174.28 | v58.5,173.28 50.43,173.28 | 46.19,154.87 46.91,155.59 | 46.96,153.87 46.18,154.65 46.33,154.65 46.37,154.69 | 47.01,154.05 46.37,154.69 | 46.37,154.69 46.19,154.87 | DVCC.1 63.13,188.98 62.94,188.79 | 51.18,173.85 52.02,173.85 | 51.61,174.54 51.61,174.46 50.71,173.56 | 50.43,173.28 50.42,173.27 | 51.59,174.57 51.74,174.41 | 51.74,174.41 52.78,173.37 | 50.43,173.28 50.71,173.56 | 50.71,173.56 50.89,173.56 51.18,173.85 | 51.61,174.28 51.74,174.41 | 51.61,174.28 51.18,173.85 | 51.13,173.85 51.18,173.85
  Bottom 1.27: 24.33,154.73 JP10.2
DVSYS_VDSYS  (via drill 0.2, 0.4, 0.5, 0.6)
  Top 0.254: 129.26,98.9 C34.1 128.23,97.88 v126.76,97.88 | C36.1 106.28,122.75 106.81,122.75 108.05,121.5 108.41,121.5 109.27,120.64 109.27,119.62 110.01,118.89 110.01,118.88 120.51,108.44 MSP430F67791A.125 120.51,99.53 122.36,97.88 v122.51,97.88 | MSP430F67791A.69 106.51,118.88 v106.26,118.62
  Top 0.406: 129.26,98.9 130.48,98.9 v131.76,97.62 | LDC_PWR.2 47.93,128.64 v56.23,120.34
  Top 0.61: DRVPWR4.1 v89.02,120.46 | v106.26,121.62 C36.1
  Bottom 0.254: v122.51,97.88 v126.76,97.88
  Bottom 0.406: v56.23,120.34 88.9,120.34 v89.02,120.46
  Bottom 0.61: v131.76,97.62 146.23,97.62 147.04,96.82 147.04,89.65 SV1.1 | v89.02,120.46 105.67,120.46 106.26,119.88 | 106.26,119.88 v106.26,118.62 | 106.26,119.88 v106.26,121.62
EN  (via drill 0.6)
  Top 0.254: U1.6 101.91,31.59 99.36,34.13 EN_SEL.2 | AD_SEL.3 107.85,39.08 107.34,39.59 100.45,39.59 99.36,38.5 v99.36,38.34
  Top 0.406: LDIG.2 19.17,120.62 20.93,118.86 20.93,48.45 24.03,45.36 80.11,45.36 v80.13,45.38 | v99.36,38.34 EN_SEL.2
  Bottom 0.406: v80.13,45.38 92.33,45.38 v99.36,38.34
EXT
  Top 0.813: JP10.3
  Top 1.016: JTAG.4 19.39,150.78 20.67,152.06 JP10.3
GND  (via drill 0.3, 0.3 pad 0.25, 0.36, 0.4, 0.5, 0.6)
  Top 0.254: MSP430F67791A.70 108.77,118.38 108.94,118.2 108.94,115.69 v109.51,115.12 | C10.2 99.15,32.48 100.3,32.48 100.53,32.25 C11.2 100.57,31.44 101.32,31.44 101.67,31.09 U1.7 103.53,31.09 U1.9 | v122.5,118.38 MSP430F67791A.33 | MSP430F67791A.120 118.01,101.78 v118.09,101.87 | MSP430F67791A.127 121.51,102.07 v121.54,102.1 | 113.37,24.01 112.44,24.93 110.67,24.93 LANLG.1 | MSP430F67791A.112 114.01,101.58 v114.27,101.85
  Top 0.406: v59.28,41.5 59.28,41.37 | 71.35,29.3 71.45,29.3 | 103.73,29.38 103.73,30.89 v103.76,30.92
  Top 0.61: C1.2 15.64,194.4 15.21,193.97 15.21,191.94 16.36,190.8 17.35,190.8 U$7.3 | 103.73,31.28 U1.9
  Top 0.813: LDIG.4 23.34,125.7 25.32,123.72 25.32,52.52 26.24,51.6 48.36,51.6 v48.38,51.58 | 59.28,41.37 59.38,41.37 71.45,29.3 71.45,29.23 72.08,28.59 101.5,28.59 102.21,29.3 C9.2
  Bottom 0.813: v59.28,41.5 49.2,51.58 v48.38,51.58
  other vias: 105.42,118.69 128.01,121.38 129.51,128.38 109.95,109.24 137.31,113.23 139.31,116.73 131.32,109.29 130.76,102.62 134.51,104.62 134.51,100.62 109.51,114.12 107.01,127.88 107.01,131.88 86.51,157.38 74.01,157.38 61.51,157.38 88.99,128.17 86.51,150.38 74.01,150.38 61.51,150.38 130.26,97.67 139.31,119.23 139.31,121.23 139.31,123.23 115.94,103.57 120.26,91.88 112.18,90.4 121.76,91.88 121.76,90.38 120.26,90.38 120.26,84.38 126.35,82.57 101.19,95.44 96.44,90.69 96.44,95.44 114.4,104.13 96.43,98.44 101.19,98.44 101.19,90.69 66.34,87.5 70.56,85.67 83.61,80.41 94.18,94.27 103.63,94.06 96.44,88.14 101.19,88.14 44.61,184.03 44.61,182.25 44.61,179.97 46.64,179.97 46.64,182.25 46.64,184.03 109.95,111.52 109.95,113.05 111.48,113.05 113.51,116.86 122.37,120.36 125.24,120.87 115.64,110.99 112.05,109.67 109.95,106.9 62.81,87.42 63.62,91.53 125.06,118.89 122.5,117.52 101.52,27.29 104.19,27.29 104.26,25.61 101.57,25.61 97.94,32.52 94.99,27.29 103.98,33.92 110.79,22.74 73.63,90.82 123.39,101.64 114.2,97.81 95.2,77.1 94.69,70.19 106.91,96.58 111.35,108.06 115.59,105.17 118.52,104.96 114.68,115.88 116.86,114.36 112.59,118.45 107.87,123.88 82.75,124.49 89.91,122.99 83.05,118.14 83.46,111.94 72.56,112.58 73.45,116.95 69.62,123.76 61.79,116.57 57.43,125.28 51.99,134.78 42.62,130.59 39.24,122.23 28.32,125.56 26.41,114.79 12.44,113.52 10.77,103.26 87.96,40.7 49.3,40.49 102.4,107.79 96.59,111.91 115.67,104.28 94.99,25.61 94.31,32.6 90.83,32.6 84.1,32.6 79.09,33.26 65.63,46.67 46.66,46.67 43.25,40.49 36.88,40.49 29.99,40.49 24.81,40.49 17.88,40.49 10.77,40.49 91.64,40.8 87.86,39.07 91.64,39.07 10.77,67.57 10.77,86.95 68.98,40.52 39.42,114.08 34.48,183.86 28.51,183.88 28.51,180.07 34.48,179.94 28.36,174.18 34.48,174.18 132.1,82.48 132.1,85.43 31.39,100.08 31.39,95.07 31.39,91.01 31.39,88.06 144.9,106.46 144.9,111.46 144.9,115.53 144.9,118.47 148.05,106.48 148.05,111.49 148.05,115.55 148.05,118.5 114.23,193.89 109.23,193.89 105.16,193.89 102.22,193.89 114.26,191.76 109.25,191.76 105.19,191.76 102.24,191.76 88.68,185.31 83.68,185.31 79.61,185.31 76.66,185.31 53.2,192.24 48.19,192.24 44.13,192.24 41.18,192.24 57.16,111.83 52.15,111.83 48.09,111.83 45.14,111.83 41.75,88.02 41.75,93.02 41.75,97.09 41.75,100.03 42.01,69.58 42.01,74.58 42.01,78.65 42.01,81.59 31.65,81.64 31.65,76.63 31.65,72.57 31.65,69.62 69.4,72.23 64.4,72.23 60.33,72.23 57.39,72.23 57.34,61.87 62.34,61.87 66.41,61.87 69.36,61.87 86.65,72.15 81.64,72.15 77.58,72.15 74.63,72.15 74.59,61.79 79.59,61.79 83.66,61.79 86.6,61.79 74.54,53.76 79.54,53.76 83.6,53.76 86.55,53.76 57.29,53.84 62.29,53.84 66.36,53.84 69.3,53.84 42.01,53.55 42.01,58.55 42.01,62.62 42.01,65.56 31.65,65.61 31.65,60.61 31.65,56.54 31.65,53.6 103.76,31.72 26.08,100.15 25.96,95.02 25.96,90.68 25.98,87.94 26.01,105.64 26.31,110.54 30.33,110.54 33.96,110.62 15.64,110.42 25.98,83.39 26.06,76.63 25.91,72.09 19.56,109.93 19.48,105.61 19.66,100.05 19.71,95.35 19.79,90.12 19.79,87.61 19.71,83.59 19.71,76.91 19.84,72.04 19.91,69.39 19.73,65.89 19.68,61.32 19.63,57.23 25.91,69.14 26.08,65.58 26.08,61.04 26.19,57.3 26.9,53.24 53.62,49.92 57.1,49.89 56.46,46.67 23.7,110.85 23.67,112.42 23.7,114.25 23.65,115.7 23.65,107.04 23.65,100.48 23.75,95.23 23.57,90.7 23.57,88.01 23.72,83.52 23.85,76.73 23.82,72.24 23.77,69.04 23.72,65.71 23.77,61.11 23.72,57.33 23.82,53.42 25.65,49.99 28.78,49.84 32.38,49.79 37.21,49.61 40.84,49.68 45.16,49.63 25.7,46.61 28.6,46.58 32.28,46.56 37.03,46.58 40.99,46.58 48.26,49.68 49.65,46.87 61.08,46.59 60.96,42.09 62.73,40.34 64.59,38.51 66.29,36.74 69.03,34.14 72.67,34.22 72.64,31.63 70.38,37.37 73.86,37.24 73.45,40.44 77.82,40.44 77.9,37.27 82.22,40.37 82.32,37.27 87.73,37.45 91.51,37.57 79.09,34.65 83.92,34.5 90.65,34.5 94.43,34.32 62.38,35.14 62.51,32.21 65.68,32.11 62.51,29.19 66.09,29.37 80.74,29.65 92.95,53.54 92.8,61.79 99.69,70.49 99.69,74.58 99.51,78.42 99.21,82 99.69,66.22 99.69,61.02 99.69,55.81 99.49,49.69 104.14,55.99 104.31,50.35 104.01,61.2 104.01,66.2 103.91,70.34 103.83,74.48 103.93,78.75 113.2,85.4 115.36,86.06 115.26,90.51 112.34,86.84 104.62,46.26 64.72,42.73 80.84,46.46 83.82,46.46 86.79,46.54 89.76,46.9 93.6,46.84 94.03,45.17 96.52,42.76 99.34,42.76 72.31,46.77 25.63,43.87 28.57,43.89 32.1,43.89 37.08,43.89 40.94,43.82 46.51,44.1 50.06,43.87 54.13,44.1 58.27,44.35 67.56,44.4 70.26,43.28 73.79,43.38 77.34,43.49 81.86,43.36 87.48,43.41 92.1,43.31
  pour Top: 11.88,195.7 118.39,195.7 118.39,158.79 150.37,158.79 150.37,79.18 106.4,79.18 106.4,26.33 112.44,26.33 112.44,22.17 90.9,22.17 90.9,27.58 60.88,27.58 60.88,37.79 3.66,37.79 3.66,164.86 11.88,164.86
  pour Bottom: 11.88,195.7 118.39,195.7 118.39,158.79 150.37,158.79 150.37,79.18 106.4,79.18 106.4,26.33 112.44,26.33 112.44,22.17 90.9,22.17 90.9,27.58 60.88,27.58 60.88,37.79 3.66,37.79 3.66,164.86 11.88,164.86
INT
  Top 1.016: JTAG.2 18.43,153.32 22.24,157.13 JP10.1
LCOM
  Top 0.254: U1.1 105.24,30.07 C9.1 106.73,29.3 108.79,27.25 110.44,27.25 LANLG.2 110.64,27.45 112.24,27.45 112.44,27.25 R11.1
LDC0851_OUT  (via drill 0.6)
  Top 0.254: MSP430F67791A.4 v121.82,103.88 | U1.5 v102.83,37.67 | v102.61,43.88 102.61,79.98 103.71,81.07 114.96,81.07 v117.6,83.71
  Top 0.406: v102.83,37.67 v102.84,37.69 | LDIG.1 18.25,117.81 18.25,46.66 21.03,43.88 21.03,43.86 22.71,42.18 57.61,42.18 59.18,43.76 66.44,43.76 68.4,41.8 100.53,41.8 v102.61,43.88
  Bottom 0.254: v117.6,83.71 117.52,83.79 117.52,98.31 117.19,98.64 117.19,103.24 117.83,103.88 v121.82,103.88
  Bottom 0.406: v102.84,37.69 102.84,43.65 v102.61,43.88 | R8.1 LDIG.1
LDC_EN_MCU  (via drill 0.6)
  Top 0.254: EN_SEL.1 101.06,37.38 v101.12,37.43 | v101.14,45.05 101.14,80.56 102.97,82.39 114.2,82.39 v114.68,82.87 | MSP430F67791A.15 122.92,109.38 121.28,111.02 119.35,111.02 v119.28,110.94
  Bottom 0.254: v119.28,110.94 117.45,110.94 116.71,110.2 116.71,84.9 v114.68,82.87 | v101.12,37.43 101.12,45.03 v101.14,45.05
LDC_VDD  (via drill 0.3 pad 0.25, 0.36 pad 0.25)
  Top 0.254: U1.8 101.86,30.59 101.42,30.14 100.57,30.14 C11.1 99.87,30.84 C10.1 99.04,30.8 | AD_SEL.1 111.25,39.9 110.06,41.09 98.19,41.09 97.66,40.56 EN_SEL.3 97.74,35.63
  Top 0.406: LED7.A 35.22,126.42 34.41,127.22 14.22,127.22 LDC_PWR.1 13.21,126 13.21,124.35 14.4,123.16 LDIG.3
  Top 0.813: LDIG.3 20.65,123.16 22.3,121.5 22.3,50.49 24.76,48.02 v56.94,48.02 | C10.1 98.99,30.75 78.48,30.75 73.53,35.7 | EN_SEL.3 73.53,35.7 | v62.71,42.77 62.71,42.49 69.49,35.7 73.53,35.7
  Bottom 0.813: v56.94,48.02 57.45,48.02 v62.71,42.77
LED1
  Top 0.254: MSP430F67791A.28 127.76,115.88 129.51,117.62 129.51,124.88 127.51,126.88 123.26,126.88 122.01,128.12 122.01,149.88 111.51,160.38 111.51,171.88 103.01,180.38 73.85,180.38 LED1.K
LED2
  Top 0.254: MSP430F67791A.27 128.01,115.38 130.01,117.38 130.01,125.12 127.76,127.38 123.51,127.38 122.51,128.38 122.51,150.12 112.01,160.62 112.01,172.12 103.26,180.88 69.27,180.88 LED2.K
LED3
  Top 0.254: MSP430F67791A.26 128.26,114.88 130.51,117.12 130.51,125.38 128.01,127.88 123.76,127.88 123.01,128.62 123.01,150.38 112.51,160.88 112.51,172.38 103.51,181.38 64.69,181.38 LED3.K
LED4
  Top 0.254: MSP430F67791A.45 119.01,145.88 110.01,154.88 110.01,171.12 102.26,178.88 90.01,178.88 88.98,177.84 LED4.K
LED5  (via drill 0.36)
  Top 0.254: MSP430F67791A.43 120.01,147.67 v118.79,148.89
  Bottom 0.254: v118.79,148.89 118.79,154.65 112.62,160.82 112.62,172.79 106.35,179.06 95.39,179.06 LED5.K
LED6  (via drill 0.36)
  Top 0.254: MSP430F67791A.44 119.51,146.47 v117.65,148.33
  Bottom 0.254: v117.65,148.33 117.65,155.03 111.86,160.82 111.86,172.33 106.32,177.87 99.28,177.87 LED6.K
LED_B
  Top 0.254: LED_B.K 85.55,179.38 102.51,179.38 110.51,171.38 110.51,159.88 120.51,149.88 MSP430F67791A.42
LEDA
  Top 0.254: MSP430F67791A.29 127.51,116.38 129.01,117.88 129.01,124.62 127.26,126.38 123.01,126.38 121.51,127.88 121.51,149.62 111.01,160.12 111.01,171.62 102.76,179.88 78.43,179.88 LED_A.K
  Bottom 0.254: 76.36,177.72 LED_A.K 76.32,177.77
LREF
  Top 0.254: U1.3 107.41,31.59 108.25,32.43 110.54,32.43 LANLG.4 113.35,32.45 R13.1
LSENSE
  Top 0.254: U1.2 107.39,31.09 108.63,29.84 110.49,29.84 LANLG.3 113.3,29.91 R12.1
N$4
  Top 0.254: R56.2 72.05,174.34 LED1.A
N$7
  Top 0.254: R55.2 66.97,174.34 LED2.A
N$10
  Top 0.254: JP4.1 27.99,136.81 22.14,136.81 21.62,137.33 R48.2
N$15  (via drill 0.6)
  Top 0.406: LED7.C 31.62,125.85 v30.53,124.76
  Bottom 0.406: v30.53,124.76 30.53,118.09 R8.2
N$16
  Top 0.254: R9.2 AD_SEL.2
N$17
  Top 0.254: R17.2 64.17,81.05 63.07,82.15 U4OUT.3
N$18
  Top 0.254: D44.A 148.54,84.02 HD1.2
N$19
  Top 0.254: R16.2 75.54,86.94 76.1,87.49 76.1,90.14 U5OUT.3
N$20
  Top 0.305: U6OUT.3 69.92,96.2 69.64,95.93 69.64,94.95 R15.2
N$21
  Top 0.254: R59.2 88.13,174.34 LED4.A
N$24
  Top 0.61: 64.21,88.62 U4GND.2 64.09,88.34 U$4.3 62.81,89.18 62.23,89.75 62.23,91.02 C52.2
N$26
  Top 0.61: U5GND.2 79.31,88.73 U$5.2
  Bottom 0.61: 79.38,88.81 U$5.2 79.13,88.56 C54.2
N$27
  Top 0.254: R60.2 93.21,174.34 LED5.A
N$28
  Top 0.61: U6GND.2 69.26,98.86 U$6.2
  Bottom 0.305: 67.59,98.89 C55.2
  Bottom 0.61: 67.59,98.89 U$6.2
N$30
  Top 0.254: R54.2 61.89,174.34 LED3.A
N$36
  Top 0.254: R61.2 98.29,174.34 LED6.A
N$41
  Top 0.61: 59.17,87.67 R45.2 59.14,87.7 59.92,87.7 60.22,87.39 U$4.2 60.48,87.38 60.48,86.71 61.37,85.81 U4OUT.2
N$43
  Top 0.61: U5OUT.2 78.09,88.79 U$5.3
  Bottom 0.61: U$5.3 78.08,90.03 R47.2
N$44
  Top 0.254: R58.2 83.05,174.34 LED_B.A
N$46
  Top 0.254: R57.2 77.13,174.34 LED_A.A
N$49
  Top 0.61: D26.A 87.06,125.21 R4.1
N$50
  Top 0.305: U$8.6 U$8.7
N$51  (via drill 0.5)
  Top 0.61: D27.A v87.22,109.59
  Bottom 0.61: v87.22,109.59 87.22,111.97 R66.1
N$52
  Top 0.61: D27.C 87.32,114.62 DRVPWR4.3 87.19,116.93 85.98,116.93 85.09,117.82 D26.C
N$53  (via drill 0.36 pad 0.25, 0.6)
  Top 0.61: DRVPWR4.2 87.78,118.76 87.81,118.79 88.97,118.79 89.51,118.25 89.51,109.95 DRV-I1.2 87.29,107.72 81.98,107.72 81.18,108.53 v28.75,108.53 | v14.09,108.6 11.17,108.6 8.35,111.42 8.35,158.26 13.69,163.59 16.74,163.59 22.88,169.74 DRV_U$7.2
  Bottom 0.61: 87.07,107.51 DRV-I1.2 | v14.09,108.6 28.67,108.6 v28.75,108.53
N$55
  Top 0.305: U6OUT.2 69.57,97.9 U$6.3
  Bottom 0.61: U$6.3 70.91,97.62 R64.2
N$58
  Top 0.305: U$8.8 68.1,88.6 R68.1 66.6,88.63 66.6,89.27 66.75,89.42 67.59,89.42 67.98,89.82 C80.1
R13  (via drill 0.2, 0.5)
  Top 0.254: MSP430F67791A.32 125.26,117.88 126.76,119.38 127.25,119.88 v128,119.88 v128.01,119.88 | R46.2 v132.26,125.38 R43.1
  Bottom 0.254: v132.26,125.38 132.26,123.36 128.88,119.98 128.11,119.98 v128.01,119.88
R23  (via drill 0.2, 0.5)
  Top 0.254: MSP430F67791A.31 125.51,117.38 126.51,118.38 v128.01,118.38 | R43.2 v132.26,121.38 R42.1
  Bottom 0.254: v132.26,121.38 132.26,121.33 129.39,118.46 128.09,118.46 v128.01,118.38
R33  (via drill 0.2, 0.5)
  Top 0.254: MSP430F67791A.30 126.51,116.88 v127.01,117.38 | v132.26,117.38 R42.2 133.16,118.53 133.88,119.25 C49.1
  Bottom 0.254: v127.01,117.38 v132.26,117.38
RESET  (via drill 0.2)
  Top 0.254: C53.2 33.66,141.81 | RESET.1 38.15,140.05 36.91,141.29 33.79,141.29 C53.2 | C53.2 32.32,141.41 31.68,140.76 31.68,140.06 31.67,140.06
  Top 0.305: C53.2 R51.2 | v31.67,135.06 31.67,140.06
  Bottom 0.254: v31.67,135.06 30.67,134.06 26.17,134.06 25.42,134.81 25.42,137.06 24.4,138.08 JP5.3 22.9,138.08 19.18,141.8 | JTAG.11 14.66,140.63 15.83,141.8 19.18,141.8 | 19.18,141.8 19.18,141.81
S0
  Top 0.254: MSP430F67791A.87 101.01,109.88 94.01,116.88 94.01,129.38 91.01,132.38 62.74,132.38 53.58,141.53 LCD1.1
S1
  Top 0.254: MSP430F67791A.86 101.26,110.38 94.51,117.12 94.51,129.62 91.26,132.88 64.76,132.88 56.1,141.53 LCD1.2
S2
  Top 0.254: MSP430F67791A.85 101.51,110.88 95.01,117.38 95.01,129.88 91.51,133.38 66.76,133.38 58.6,141.53 LCD1.3
S3
  Top 0.254: MSP430F67791A.84 101.76,111.38 95.51,117.62 95.51,130.12 91.76,133.88 68.76,133.88 LCD1.4
S4
  Top 0.254: MSP430F67791A.83 102.01,111.88 96.01,117.88 96.01,130.38 92.01,134.38 70.76,134.38 63.64,141.49 LCD1.5
S5
  Top 0.254: MSP430F67791A.82 102.26,112.38 96.51,118.12 96.51,130.62 92.26,134.88 72.76,134.88 66.18,141.45 LCD1.6
S6
  Top 0.254: MSP430F67791A.81 102.51,112.88 97.01,118.38 97.01,130.88 92.51,135.38 74.76,135.38 68.72,141.41 LCD1.7
S7
  Top 0.254: MSP430F67791A.80 102.76,113.38 97.51,118.62 97.51,131.12 92.76,135.88 76.76,135.88 71.26,141.37 LCD1.8
S8
  Top 0.254: MSP430F67791A.79 103.01,113.88 98.01,118.88 98.01,131.38 93.01,136.38 78.76,136.38 73.8,141.33 LCD1.9
S9
  Top 0.254: MSP430F67791A.78 103.26,114.38 98.51,119.12 98.51,131.62 93.26,136.88 80.76,136.88 76.34,141.29 LCD1.10
S10
  Top 0.254: MSP430F67791A.77 103.51,114.88 99.01,119.38 99.01,131.88 93.51,137.38 82.76,137.38 78.88,141.25 LCD1.11
S11
  Top 0.254: MSP430F67791A.76 103.76,115.38 99.51,119.62 99.51,132.12 93.76,137.88 84.76,137.88 81.42,141.21 LCD1.12
S12
  Top 0.254: MSP430F67791A.75 104.01,115.88 100.01,119.88 100.01,132.38 94.01,138.38 86.76,138.38 83.96,141.2 LCD1.13
S13
  Top 0.254: MSP430F67791A.74 104.26,116.38 100.51,120.12 100.51,132.62 94.26,138.88 88.76,138.88 86.5,141.13 LCD1.14
S14
  Top 0.254: MSP430F67791A.73 104.51,116.88 101.01,120.38 101.01,132.88 94.51,139.38 90.76,139.38 89.04,141.12 LCD1.15
S15
  Top 0.254: MSP430F67791A.72 104.76,117.38 101.51,120.62 101.51,133.12 94.76,139.88 92.76,139.88 91.58,141.08 LCD1.16
S16
  Top 0.254: MSP430F67791A.71 105.01,117.88 102.01,120.88 102.01,133.38 94.12,141.29 LCD1.17
S17
  Top 0.254: MSP430F67791A.68 104.26,119.38 102.51,121.12 102.51,133.62 96.66,139.43 LCD1.18
S18
  Top 0.254: MSP430F67791A.67 104.51,119.88 103.01,121.38 103.01,133.88 99.2,137.71 LCD1.19
S19
  Top 0.254: MSP430F67791A.66 104.76,120.38 103.51,121.62 103.51,134.12 101.74,135.92 LCD1.20
S20
  Top 0.254: MSP430F67791A.65 105.01,120.88 104.01,121.88 104.01,141.26 LCD1.21
S21
  Top 0.254: MSP430F67791A.64 109.51,140.88 109.01,141.38 108.81,141.57 106.86,141.57 LCD1.22
S22  (via drill 0.36)
  Top 0.254: MSP430F67791A.63 110.01,141.38 107.01,144.38 v106.51,144.38
  Bottom 0.254: v106.51,144.38 106.51,171.19 LCD1.23
S23  (via drill 0.36)
  Top 0.254: MSP430F67791A.62 110.51,141.62 106.76,145.38 v105.51,145.38
  Bottom 0.254: v105.51,145.38 105.51,170.28 LCD1.24
S24  (via drill 0.36)
  Top 0.254: MSP430F67791A.61 111.01,141.88 106.51,146.38 v104.51,146.38
  Bottom 0.254: v104.51,146.38 104.51,158.38 91.58,171.26 LCD1.29
S25  (via drill 0.36)
  Top 0.254: MSP430F67791A.60 111.51,142.12 106.26,147.38 v103.51,147.38
  Bottom 0.254: v103.51,147.38 103.51,158.62 93.26,168.88 91.51,168.88 89.04,171.34 LCD1.30
S26  (via drill 0.36)
  Top 0.254: MSP430F67791A.59 112.01,142.38 106.01,148.38 v102.51,148.38
  Bottom 0.254: v102.51,148.38 102.51,158.88 93.01,168.38 89.51,168.38 86.5,171.38 LCD1.31
S27  (via drill 0.36)
  Top 0.254: MSP430F67791A.58 112.51,142.62 105.76,149.38 v101.51,149.38
  Bottom 0.254: v101.51,149.38 101.51,159.12 92.76,167.88 87.51,167.88 83.96,171.42 LCD1.32
S28  (via drill 0.36)
  Top 0.254: MSP430F67791A.57 113.01,142.88 105.51,150.38 v100.51,150.38
  Bottom 0.254: v100.51,150.38 100.51,159.38 92.51,167.38 85.51,167.38 81.42,171.46 LCD1.33
S29  (via drill 0.36)
  Top 0.254: MSP430F67791A.56 113.51,143.12 105.26,151.38 v99.51,151.38
  Bottom 0.254: v99.51,151.38 99.51,159.62 92.26,166.88 83.51,166.88 LCD1.34
S30  (via drill 0.36)
  Top 0.254: MSP430F67791A.55 114.01,143.38 105.01,152.38 v98.51,152.38
  Bottom 0.254: v98.51,152.38 98.51,159.88 92.01,166.38 81.51,166.38 76.38,171.5 LCD1.35
S31  (via drill 0.36)
  Top 0.254: MSP430F67791A.54 114.51,143.62 104.76,153.38 v97.51,153.38
  Bottom 0.254: v97.51,153.38 97.51,160.12 91.76,165.88 79.51,165.88 73.88,171.5 LCD1.36
S32  (via drill 0.36)
  Top 0.254: MSP430F67791A.53 115.01,143.88 104.51,154.38 v96.51,154.38
  Bottom 0.254: v96.51,154.38 96.51,160.38 91.51,165.38 77.51,165.38 71.38,171.5 LCD1.37
S33  (via drill 0.36)
  Top 0.254: MSP430F67791A.52 115.51,144.12 104.26,155.38 v95.51,155.38
  Bottom 0.254: v95.51,155.38 95.51,160.62 91.26,164.88 75.51,164.88 68.88,171.5 LCD1.38
S34  (via drill 0.36)
  Top 0.254: MSP430F67791A.51 116.01,144.38 104.01,156.38 v94.51,156.38
  Bottom 0.254: v94.51,156.38 94.51,160.88 91.01,164.38 73.26,164.38 66.18,171.45 LCD1.39
S35  (via drill 0.36)
  Top 0.254: MSP430F67791A.50 116.51,144.62 103.76,157.38 v93.51,157.38
  Bottom 0.254: v93.51,157.38 93.51,161.12 90.76,163.88 71.26,163.88 LCD1.40
S36  (via drill 0.36)
  Top 0.254: MSP430F67791A.49 117.01,144.88 103.51,158.38 v92.51,158.38
  Bottom 0.254: v92.51,158.38 92.51,161.38 90.51,163.38 69.26,163.38 61.13,171.5 LCD1.41
S37  (via drill 0.36)
  Top 0.254: MSP430F67791A.48 117.51,145.12 103.26,159.38 v91.51,159.38
  Bottom 0.254: v91.51,159.38 91.51,161.62 90.26,162.88 67.26,162.88 58.63,171.5 LCD1.42
S38  (via drill 0.36)
  Top 0.254: MSP430F67791A.47 118.01,145.38 103.01,160.38 v90.51,160.38
  Bottom 0.254: v90.51,160.38 90.51,161.88 90.01,162.38 65.26,162.38 56.13,171.5 LCD1.43
S39  (via drill 0.36)
  Top 0.254: MSP430F67791A.46 118.51,145.62 102.76,161.38 v89.51,161.38
  Bottom 0.254: v89.51,161.38 89.01,161.88 63.01,161.88 53.48,171.4 LCD1.44
TCK
  Top 0.254: R48.1 21.62,140.09 22.14,140.62 JP6.3
  Bottom 0.254: JP6.3 22.91,140.62 19.1,144.43 15.92,144.43 JTAG.7
TDI
  Bottom 0.254: JP8.3 22.91,145.7 19.05,149.56 15.88,149.56 JTAG.3
TDO
  Top 0.254: JP9.3 25.45,146.97 27.36,146.97 27.99,146.33 27.99,139.35 JP5.1
  Bottom 0.254: JP9.3 22.91,148.24 19.1,152.05 15.93,152.05 JTAG.1
TEST/SBWTCK  (via drill 0.36)
  Top 0.254: JTAG.8 19.1,143.79 19.1,135.54 20.37,134.27 22.91,134.27 JP4.3 JP4.2 26.72,135.51 27.82,134.41 28.17,134.06 28.2,134.03 33.27,134.03 36.12,136.88 55.54,136.88 60.58,131.83 90.76,131.88 93.51,129.12 93.51,116.12 94.55,115.08 v94.74,115.08 | MSP430F67791A.97 101.51,104.88 v100.88,104.25
  Bottom 0.254: v100.88,104.25 100.81,104.18 99.06,104.18 95.25,107.99 95.25,114.57 v94.74,115.08
TMS
  Bottom 0.254: JP7.3 22.91,143.16 19.14,146.93 15.96,146.93 JTAG.5
VASYS1/2
  Top 0.254: C23.1 112.01,94.12 111.86,93.97 C22.1 110.51,94.88 113.51,97.88 MSP430F67791A.111 113.51,101.47 112.8,102.18 112.8,102.53 113.14,102.88 118.51,102.88 119.01,102.38 MSP430F67791A.122 119.01,98.48 120.61,96.88 122.51,96.88 122.75,96.64 C32.1
  Top 0.406: C32.1 122.75,95.64 122.76,95.62 C28.1
VCORE
  Top 0.254: C38.1 123.51,100.38 123.51,100.58 MSP430F67791A.128
VREF
  Top 0.254: C30.1 115.11,98.83 114.51,99.43 MSP430F67791A.113
XIN
  Top 0.254: MSP430F67791A.1 126.01,102.38 126.86,101.53 128.41,101.53 XT1.P2 130.51,101.38 131.41,100.47 C37.1 131.41,99.97
XOUT
  Top 0.254: XT1.P1 128.41,104.06 | MSP430F67791A.2 126.01,102.88 127.01,103.88 XT1.P1 | XT1.P1 130.55,103.88 131.37,104.69 131.37,105.34 C40.1

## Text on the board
tNames: + | + | + | + | + | + | + | + | M. MESGANAW / MARCH 2017 | DVCC | INTERNAL | EXTERNAL | TIDA-01377 | J=JTAG | J | S | S=SBW | Version 1.0, 1 coil set implementation | GND | VDD | ENABLE | OUT | AUXVCC1 | AUXVCC2 | AUXVCC3 | DGND | DGND | VDSYS | REF | SENSE | COM | GND
_tplace: C1 | U$7 | DVCC | DRV_U$7 | R1 | DGND | 1 | LED3 | LED2 | LED1 | LED_A | LED_B | LED4 | LED5 | LED6 | R54 | + | R55 | + | R56 | + | R57 | + | R58 | + | R59 | + | R60 | + | R61 | + | M. MESGANAW / MARCH 2017 | DVCC | 1 | 2 | INTERNAL | DBTN1 | EXTERNAL | RESET | TIDA-01377 | 14 | LCD1 | R53 | R51 | DBTN2 | R48 | C53 | J=JTAG | J | S | S=SBW | JTAG | R50 | LDIG | Version 1.0, 1 coil set implementation | R46 | LDC_PWR | GND | LED7 | C58 | VDD | R4 | C36 | D26 | R43 | ENABLE | C49 | OUT | R42 | 1 | DRVPWR4 | D27 | MSP430F67791A | C43 | C44 | C40 | DRV-I1 | 1 | U$6 | C38 | XT1 | C34 | C35 | C37 | U6GND | C30 | C33 | U4GND | 1 | U6OUT | C31 | C32 | 1 | C22 | C23 | C29 | C28 | C52 | C15 | R15 | 1 | C24 | C25 | C26 | C27 | AUXVCC1 | AUXVCC2 | AUXVCC3 | U5OUT | R45 | 1 | C80 | C14 | 1 | D44 | 1 | U$5 | R68 | U$4 | U$8 | 1 | R36 | DGND | DGND | VDSYS | 1 | 1 | R16 | U5GND | U4OUT | HD1 | C12 | R17 | AD_SEL | 1 | EN_SEL | 1 | R10 | R9 | U1 | R13 | REF | SENSE | R12 | C9 | C10 | C11 | R11 | COM | LANLG | GND
_bplace: R8 | R66 | C55 | R64 | R47 | C54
